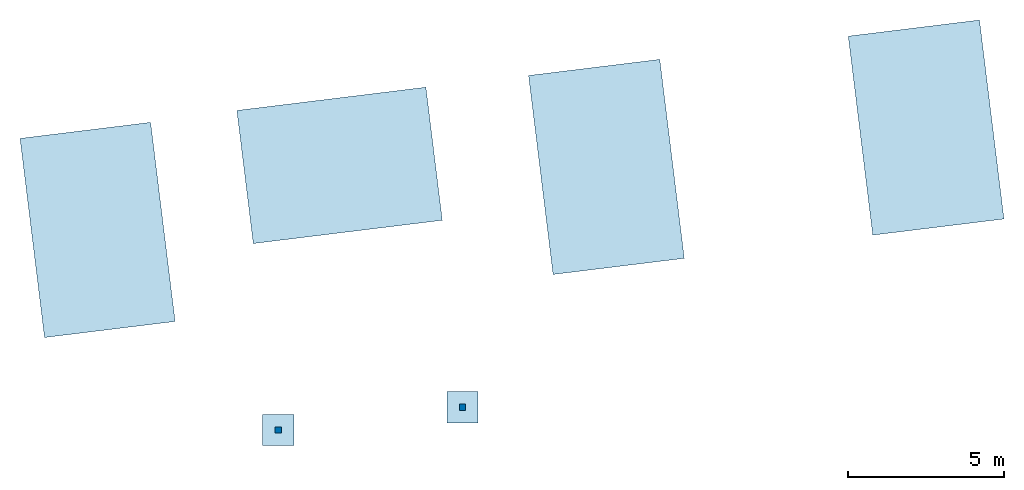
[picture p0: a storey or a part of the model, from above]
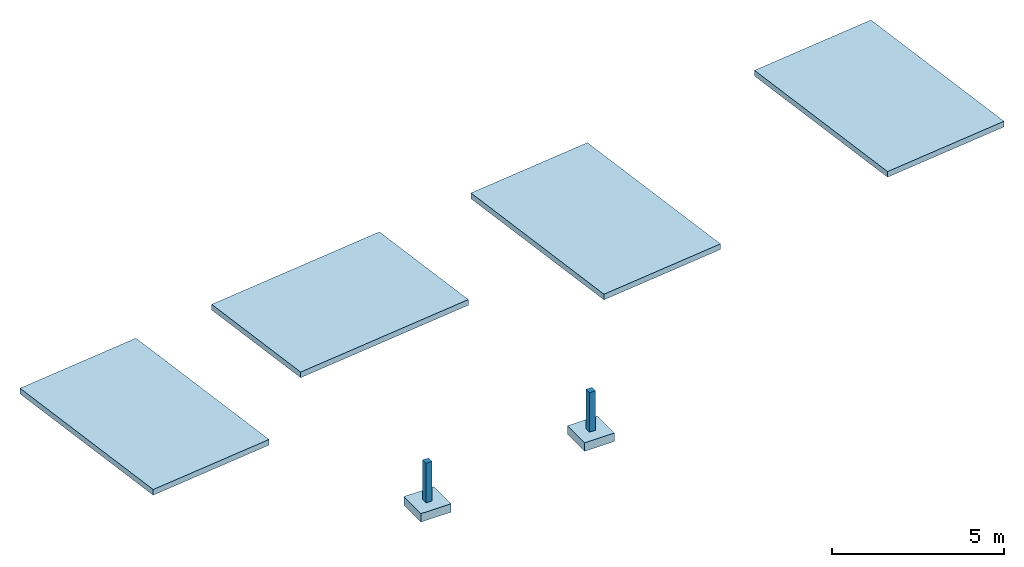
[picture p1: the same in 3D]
Properties of the parts of a building model (IFC2X3)

# File
Description: ViewDefinition [CoordinationView]
Time: 2023-04-20T00:44:39
Made in: SketchUp Pro 2015

# IfcProject, 1013 - PRAÇA - RANCHO QUEIMADO
Description: 1013 - PRAÇA - RANCHO QUEIMADO

# IfcSite, Default Site
Description: Description of Default Site; RefLatitude: 24, 28, 0; RefLongitude: 54, 25, 0; RefElevation: 10 mm

# IfcBuilding, Default Building
Description: Description of Default Building

# IfcBuildingStorey (3)
In: Default Building
Description: Description of Default Building Storey; Elevation: 0 mm

# IfcBeam (4)
In: Fundação
Description: Description of Object
Description - IfcText: Retangular. Concreto armado
PSet_BeamCommon - isExternal: no; isLoadBearing: yes
Name | ObjectType, IfcLabel | Name, IfcLabel
IfcBeam - IfcBeam - Viga 118 (60x150) | 60x150 | Viga 118 (60x150)
IfcBeam - Viga 123 (30x70) | 30x70 | Viga 123 (30x70)
IfcBeam - Viga 122 (30x70) | 30x70 | Viga 122 (30x70)
IfcBeam - Viga 124 (30x70) | 30x70 | Viga 124 (30x70)

# IfcColumn (8)
In: Fundação
Description: Description of Object
Description - IfcText: Retangular. Concreto armado
PSet_ColumnCommon - isExternal: no; isLoadBearing: yes
Qto_ColumnBaseQuantities - Length: 1200
Name | ObjectType, IfcLabel | Name, IfcLabel | Reference
IfcColumn - IfcColumn - P1 (20x20) | 20x20 | P1 (20x20) | P1
IfcColumn - IfcColumn - P2 (20x20) | 20x20 | P2 (20x20) | P2
IfcColumn - P6 (40x40) | 40x40 | P6 (40x40) | P6
IfcColumn - P5 (40x40) | 40x40 | P5 (40x40) | P5
IfcColumn - P8 (40x40) | 40x40 | P8 (40x40) | P8
IfcColumn - P3 (40x40) | 40x40 | P3 (40x40) | P3
IfcColumn - P4 (40x40) | 40x40 | P4 (40x40) | P4
IfcColumn - P7 (40x40) | 40x40 | P7 (40x40) | P7

# IfcFooting (131)
In: Fundação
Description: Description of Object
PredefinedType - IfcFootingTypeEnum: footing_beam
Name | ObjectType, IfcLabel | Name, IfcLabel | IfcText
IfcFooting - IfcFooting - P1 (100 x 100 x 30) | 100 x 100 x 30 | P1 (100 x 100 x 30) | Sapata em concreto armado
IfcFooting - IfcFooting - P2 (100 x 100 x 30) | 100 x 100 x 30 | P2 (100 x 100 x 30) | Sapata em concreto armado
IfcFooting - IfcFooting - Viga 34 (50x30) | 50x30 | Viga 34 (50x30) | Retangular. Concreto armado
IfcFooting - IfcFooting - Viga 23 (50x30) | 50x30 | Viga 23 (50x30) | Retangular. Concreto armado
IfcFooting - IfcFooting - Viga 26 (50x30) | 50x30 | Viga 26 (50x30) | Retangular. Concreto armado
IfcFooting - IfcFooting - Viga 31 (50x30) | 50x30 | Viga 31 (50x30) | Retangular. Concreto armado
IfcFooting - IfcFooting - Viga 39 (50x30) | 50x30 | Viga 39 (50x30) | Retangular. Concreto armado
IfcFooting - IfcFooting - Viga 35 (50x30) | 50x30 | Viga 35 (50x30) | Retangular. Concreto armado
IfcFooting - IfcFooting - Viga 36 (50x30) | 50x30 | Viga 36 (50x30) | Retangular. Concreto armado
IfcFooting - IfcFooting - Viga 42 (50x30) | 50x30 | Viga 42 (50x30) | Retangular. Concreto armado
IfcFooting - IfcFooting - Viga 25 (50x30) | 50x30 | Viga 25 (50x30) | Retangular. Concreto armado
IfcFooting - IfcFooting - Viga 28 (50x30) | 50x30 | Viga 28 (50x30) | Retangular. Concreto armado
IfcFooting - IfcFooting - Viga 43 (50x30) | 50x30 | Viga 43 (50x30) | Retangular. Concreto armado
IfcFooting - IfcFooting - Viga 29 (50x30) | 50x30 | Viga 29 (50x30) | Retangular. Concreto armado
IfcFooting - IfcFooting - Viga 40 (50x30) | 50x30 | Viga 40 (50x30) | Retangular. Concreto armado
IfcFooting - IfcFooting - Viga 33 (50x30) | 50x30 | Viga 33 (50x30) | Retangular. Concreto armado
IfcFooting - IfcFooting - Viga 38 (50x30) | 50x30 | Viga 38 (50x30) | Retangular. Concreto armado
IfcFooting - IfcFooting - Viga 37 (50x30) | 50x30 | Viga 37 (50x30) | Retangular. Concreto armado
IfcFooting - IfcFooting - Viga 24 (50x30) | 50x30 | Viga 24 (50x30) | Retangular. Concreto armado
IfcFooting - IfcFooting - Viga 44 (50x30) | 50x30 | Viga 44 (50x30) | Retangular. Concreto armado
IfcFooting - IfcFooting - Viga 30 (50x30) | 50x30 | Viga 30 (50x30) | Retangular. Concreto armado
IfcFooting - IfcFooting - Viga 27 (50x30) | 50x30 | Viga 27 (50x30) | Retangular. Concreto armado
IfcFooting - IfcFooting - Viga 32 (50x30) | 50x30 | Viga 32 (50x30) | Retangular. Concreto armado
IfcFooting - IfcFooting - Viga 41 (50x30) | 50x30 | Viga 41 (50x30) | Retangular. Concreto armado
IfcFooting - IfcFooting - Viga 45 (50x30) | 50x30 | Viga 45 (50x30) | Retangular. Concreto armado
IfcFooting - IfcFooting - Viga 119 (60x100) |  | Viga 119 (60x100) | Retangular. Concreto armado
IfcFooting - IfcFooting - Viga 83 (50x30) | 50x30 | Viga 83 (50x30) | Retangular. Concreto armado
IfcFooting - IfcFooting - Viga 82 (50x30) | 50x30 | Viga 82 (50x30) | Retangular. Concreto armado
IfcFooting - IfcFooting - Viga 87 (50x30) | 50x30 | Viga 87 (50x30) | Retangular. Concreto armado
IfcFooting - IfcFooting - Viga 94 (50x30) | 50x30 | Viga 94 (50x30) | Retangular. Concreto armado
IfcFooting - IfcFooting - Viga 91 (50x30) | 50x30 | Viga 91 (50x30) | Retangular. Concreto armado
2 x IfcFooting - IfcFooting - Viga 85 (50x30) | 50x30 | Viga 85 (50x30) | Retangular. Concreto armado
IfcFooting - IfcFooting - Viga 86 (50x30) | 50x30 | Viga 86 (50x30) | Retangular. Concreto armado
IfcFooting - IfcFooting - Viga 92 (50x30) | 50x30 | Viga 92 (50x30) | Retangular. Concreto armado
IfcFooting - IfcFooting - Viga 84 (50x30) | 50x30 | Viga 84 (50x30) | Retangular. Concreto armado
IfcFooting - IfcFooting - Viga 88 (50x30) | 50x30 | Viga 88 (50x30) | Retangular. Concreto armado
IfcFooting - IfcFooting - Viga 89 (50x30) | 50x30 | Viga 89 (50x30) | Retangular. Concreto armado
IfcFooting - IfcFooting - Viga 90 (50x30) | 50x30 | Viga 90 (50x30) | Retangular. Concreto armado
IfcFooting - IfcFooting - Viga 81 (50x30) | 50x30 | Viga 81 (50x30) | Retangular. Concreto armado
IfcFooting - IfcFooting - Viga 93 (50x30) | 50x30 | Viga 93 (50x30) | Retangular. Concreto armado
IfcFooting - IfcFooting - Viga 80 (50x30) | 50x30 | Viga 80 (50x30) | Retangular. Concreto armado
IfcFooting - IfcFooting - Viga 74 (50x30) | 50x30 | Viga 74 (50x30) | Retangular. Concreto armado
IfcFooting - IfcFooting - Viga 75 (50x30) | 50x30 | Viga 75 (50x30) | Retangular. Concreto armado
IfcFooting - IfcFooting - Viga 72 (50x30) | 50x30 | Viga 72 (50x30) | Retangular. Concreto armado
IfcFooting - IfcFooting - Viga 71 (50x30) | 50x30 | Viga 71 (50x30) | Retangular. Concreto armado
IfcFooting - IfcFooting - Viga 73 (50x30) | 50x30 | Viga 73 (50x30) | Retangular. Concreto armado
IfcFooting - IfcFooting - Viga 78 (50x30) | 50x30 | Viga 78 (50x30) | Retangular. Concreto armado
IfcFooting - IfcFooting - Viga 76 (50x30) | 50x30 | Viga 76 (50x30) | Retangular. Concreto armado
IfcFooting - IfcFooting - Viga 79 (50x30) | 50x30 | Viga 79 (50x30) | Retangular. Concreto armado
IfcFooting - IfcFooting - Viga 77 (50x30) | 50x30 | Viga 77 (50x30) | Retangular. Concreto armado
IfcFooting - IfcFooting - Viga 70 (50x30) | 50x30 | Viga 70 (50x30) | Retangular. Concreto armado
IfcFooting - IfcFooting - Viga 49 (110/30) | 110/30 | Viga 49 (110/30) | Viga de fundação. Concreto armado
IfcFooting - IfcFooting - Viga 51 (110/30) | 110/30 | Viga 51 (110/30) | Viga de fundação. Concreto armado
IfcFooting - IfcFooting - Viga 47 (110/30) | 110/30 | Viga 47 (110/30) | Viga de fundação. Concreto armado
IfcFooting - IfcFooting - Viga 50 (110/30) | 110/30 | Viga 50 (110/30) | Viga de fundação. Concreto armado
IfcFooting - IfcFooting - Viga 46 (110/30) | 110/30 | Viga 46 (110/30) | Viga de fundação. Concreto armado
IfcFooting - IfcFooting - Viga 53 (110/30) | 110/30 | Viga 53 (110/30) | Viga de fundação. Concreto armado
IfcFooting - IfcFooting - Viga 48 (110/30) | 110/30 | Viga 48 (110/30) | Viga de fundação. Concreto armado
IfcFooting - IfcFooting - Viga 52 (110/30) | 110/30 | Viga 52 (110/30) | Viga de fundação. Concreto armado
IfcFooting - IfcFooting - Viga 65 (110/30) | 110/30 | Viga 65 (110/30) | Viga de fundação. Concreto armado
IfcFooting - IfcFooting - Viga 66 (110/30) | 110/30 | Viga 66 (110/30) | Viga de fundação. Concreto armado
IfcFooting - IfcFooting - Viga 67 (110/30) | 110/30 | Viga 67 (110/30) | Viga de fundação. Concreto armado
IfcFooting - IfcFooting - Viga 64 (110/30) | 110/30 | Viga 64 (110/30) | Viga de fundação. Concreto armado
IfcFooting - IfcFooting - Viga 54 (110/30) | 110/30 | Viga 54 (110/30) | Viga de fundação. Concreto armado
IfcFooting - IfcFooting - Viga 62 (110/30) | 110/30 | Viga 62 (110/30) | Viga de fundação. Concreto armado
IfcFooting - IfcFooting - Viga 55 (110/30) | 110/30 | Viga 55 (110/30) | Viga de fundação. Concreto armado
IfcFooting - IfcFooting - Viga 63 (110/30) | 110/30 | Viga 63 (110/30) | Viga de fundação. Concreto armado
IfcFooting - IfcFooting - Viga 60 (110/30) | 110/30 | Viga 60 (110/30) | Viga de fundação. Concreto armado
IfcFooting - IfcFooting - Viga 58 (110/30) | 110/30 | Viga 58 (110/30) | Viga de fundação. Concreto armado
IfcFooting - IfcFooting - Viga 61 (110/30) | 110/30 | Viga 61 (110/30) | Viga de fundação. Concreto armado
IfcFooting - IfcFooting - Viga 68 (110/30) | 110/30 | Viga 68 (110/30) | Viga de fundação. Concreto armado
IfcFooting - IfcFooting - Viga 59 (110/30) | 110/30 | Viga 59 (110/30) | Viga de fundação. Concreto armado
IfcFooting - IfcFooting - Viga 69 (110/30) | 110/30 | Viga 69 (110/30) | Viga de fundação. Concreto armado
IfcFooting - IfcFooting - Viga 56 (110/30) | 110/30 | Viga 56 (110/30) | Viga de fundação. Concreto armado
IfcFooting - IfcFooting - Viga 57 (110/30) | 110/30 | Viga 57 (110/30) | Viga de fundação. Concreto armado
IfcFooting - IfcFooting - Viga 197 (110/30) | 110/30 | Viga 197 (110/30) | Viga de fundação. Concreto armado
IfcFooting - IfcFooting - Viga 198 (110/30) | 110/30 | Viga 198 (110/30) | Viga de fundação. Concreto armado
IfcFooting - IfcFooting - Viga 195 (110/30) | 110/30 | Viga 195 (110/30) | Viga de fundação. Concreto armado
IfcFooting - IfcFooting - Viga 196 (110/30) | 110/30 | Viga 196 (110/30) | Viga de fundação. Concreto armado
IfcFooting - IfcFooting - Viga 1 (110/30) | 110/30 | Viga 1 (110/30) | Viga de fundação. Concreto armado
IfcFooting - IfcFooting - Viga 12 (110/30) | 110/30 | Viga 12 (110/30) | Viga de fundação. Concreto armado
IfcFooting - IfcFooting - Viga 7 (110/30) | 110/30 | Viga 7 (110/30) | Viga de fundação. Concreto armado
IfcFooting - IfcFooting - Viga 17 (110/30) | 110/30 | Viga 17 (110/30) | Viga de fundação. Concreto armado
IfcFooting - IfcFooting - Viga 2 (110/30) | 110/30 | Viga 2 (110/30) | Viga de fundação. Concreto armado
IfcFooting - IfcFooting - Viga 4 (110/30) | 110/30 | Viga 4 (110/30) | Viga de fundação. Concreto armado
IfcFooting - IfcFooting - Viga 8 (110/30) | 110/30 | Viga 8 (110/30) | Viga de fundação. Concreto armado
IfcFooting - IfcFooting - Viga 22 (110/30) | 110/30 | Viga 22 (110/30) | Viga de fundação. Concreto armado
IfcFooting - IfcFooting - Viga 20 (110/30) | 110/30 | Viga 20 (110/30) | Viga de fundação. Concreto armado
IfcFooting - IfcFooting - Viga 9 (110/30) | 110/30 | Viga 9 (110/30) | Viga de fundação. Concreto armado
IfcFooting - IfcFooting - Viga 21 (110/30) | 110/30 | Viga 21 (110/30) | Viga de fundação. Concreto armado
IfcFooting - IfcFooting - Viga 14 (110/30) | 110/30 | Viga 14 (110/30) | Viga de fundação. Concreto armado
IfcFooting - IfcFooting - Viga 15 (110/30) | 110/30 | Viga 15 (110/30) | Viga de fundação. Concreto armado
IfcFooting - IfcFooting - Viga 6 (110/30) | 110/30 | Viga 6 (110/30) | Viga de fundação. Concreto armado
IfcFooting - IfcFooting - Viga 16 (110/30) | 110/30 | Viga 16 (110/30) | Viga de fundação. Concreto armado
IfcFooting - IfcFooting - Viga 3 (110/30) | 110/30 | Viga 3 (110/30) | Viga de fundação. Concreto armado
IfcFooting - IfcFooting - Viga 19 (110/30) | 110/30 | Viga 19 (110/30) | Viga de fundação. Concreto armado
IfcFooting - IfcFooting - Viga 5 (110/30) | 110/30 | Viga 5 (110/30) | Viga de fundação. Concreto armado
IfcFooting - IfcFooting - Viga 13 (110/30) | 110/30 | Viga 13 (110/30) | Viga de fundação. Concreto armado
IfcFooting - IfcFooting - Viga 18 (110/30) | 110/30 | Viga 18 (110/30) | Viga de fundação. Concreto armado
IfcFooting - IfcFooting - Viga 11 (110/30) | 110/30 | Viga 11 (110/30) | Viga de fundação. Concreto armado
IfcFooting - IfcFooting - Viga 10 (110/30) | 110/30 | Viga 10 (110/30) | Viga de fundação. Concreto armado
IfcFooting - IfcFooting - Viga 113 (110/30) | 110/30 | Viga 113 (110/30) | Viga de fundação. Concreto armado
IfcFooting - IfcFooting - Viga 103 (110/30) | 110/30 | Viga 103 (110/30) | Viga de fundação. Concreto armado
IfcFooting - IfcFooting - Viga 112 (110/30) | 110/30 | Viga 112 (110/30) | Viga de fundação. Concreto armado
IfcFooting - IfcFooting - Viga 100 (110/30) | 110/30 | Viga 100 (110/30) | Viga de fundação. Concreto armado
IfcFooting - IfcFooting - Viga 99 (110/30) | 110/30 | Viga 99 (110/30) | Viga de fundação. Concreto armado
IfcFooting - IfcFooting - Viga 111 (110/30) | 110/30 | Viga 111 (110/30) | Viga de fundação. Concreto armado
IfcFooting - IfcFooting - Viga 101 (110/30) | 110/30 | Viga 101 (110/30) | Viga de fundação. Concreto armado
IfcFooting - IfcFooting - Viga 109 (110/30) | 110/30 | Viga 109 (110/30) | Viga de fundação. Concreto armado
IfcFooting - IfcFooting - Viga 102 (110/30) | 110/30 | Viga 102 (110/30) | Viga de fundação. Concreto armado
IfcFooting - IfcFooting - Viga 110 (110/30) | 110/30 | Viga 110 (110/30) | Viga de fundação. Concreto armado
IfcFooting - IfcFooting - Viga 96 (110/30) | 110/30 | Viga 96 (110/30) | Viga de fundação. Concreto armado
IfcFooting - IfcFooting - Viga 115 (110/30) | 110/30 | Viga 115 (110/30) | Viga de fundação. Concreto armado
IfcFooting - IfcFooting - Viga 98 (110/30) | 110/30 | Viga 98 (110/30) | Viga de fundação. Concreto armado
IfcFooting - IfcFooting - Viga 104 (110/30) | 110/30 | Viga 104 (110/30) | Viga de fundação. Concreto armado
IfcFooting - IfcFooting - Viga 108 (110/30) | 110/30 | Viga 108 (110/30) | Viga de fundação. Concreto armado
IfcFooting - IfcFooting - Viga 117 (110/30) | 110/30 | Viga 117 (110/30) | Viga de fundação. Concreto armado
IfcFooting - IfcFooting - Viga 114 (110/30) | 110/30 | Viga 114 (110/30) | Viga de fundação. Concreto armado
IfcFooting - IfcFooting - Viga 107 (110/30) | 110/30 | Viga 107 (110/30) | Viga de fundação. Concreto armado
IfcFooting - IfcFooting - Viga 116 (110/30) | 110/30 | Viga 116 (110/30) | Viga de fundação. Concreto armado
IfcFooting - IfcFooting - Viga 105 (110/30) | 110/30 | Viga 105 (110/30) | Viga de fundação. Concreto armado
IfcFooting - IfcFooting - Viga 95 (110/30) | 110/30 | Viga 95 (110/30) | Viga de fundação. Concreto armado
IfcFooting - IfcFooting - Viga 106 (110/30) | 110/30 | Viga 106 (110/30) | Viga de fundação. Concreto armado
IfcFooting - IfcFooting - Viga 97 (110/30) | 110/30 | Viga 97 (110/30) | Viga de fundação. Concreto armado
IfcFooting - P3 (150 x 150 x 30) | 150 x 150 x 30 | P3 (150 x 150 x 30) | Sapata em concreto armado
IfcFooting - P7 (150 x 150 x 30) | 150 x 150 x 30 | P7 (150 x 150 x 30) | Sapata em concreto armado
IfcFooting - P5 (150 x 150 x 30) | 150 x 150 x 30 | P5 (150 x 150 x 30) | Sapata em concreto armado
IfcFooting - P8 (150 x 150 x 30) | 150 x 150 x 30 | P8 (150 x 150 x 30) | Sapata em concreto armado
IfcFooting - P6 (150 x 150 x 30) | 150 x 150 x 30 | P6 (150 x 150 x 30) | Sapata em concreto armado
IfcFooting - P4 (150 x 150 x 30) | 150 x 150 x 30 | P4 (150 x 150 x 30) | Sapata em concreto armado

# IfcSlab (4)
In: Fundação
Description: Description of Object
PredefinedType - IfcSlabTypeEnum: floor
ObjectType - IfcLabel: Lajes de fundação: 20
Description - IfcText: Lajes de fundação
PSet_SlabCommon - isExternal: no; isLoadBearing: yes
Qto_SlabBaseQuantities - Width: 200
Name | IfcLabel | ConcreteSurface = GrossArea = NetArea | ConcreteVolume = GrossVolume = NetVolume | Perimeter | GrossWeight = NetWeight
IfcSlab - IfcSlab - Pano 2 (20 cm) | Pano 2 (20 cm) | 27.0783 | 5.41566 | 21279 | 13539.2
IfcSlab - IfcSlab - Pano 3 (20 cm) | Pano 3 (20 cm) | 26.1966 | 5.23932 | 20789 | 13098.3
IfcSlab - IfcSlab - Pano 4 (20 cm) | Pano 4 (20 cm) | 27.189 | 5.4378 | 21310.1 | 13594.5
IfcSlab - IfcSlab - Pano 5 (20 cm) | Pano 5 (20 cm) | 27.189 | 5.4378 | 21310.1 | 13594.5

# IfcWallStandardCase (121)
In: Fundação
Description: Description of Object
Description - IfcText: Cortina de concreto armado
PSet_WallCommon - isExternal: no; isLoadBearing: yes
Name | ObjectType, IfcLabel | Name, IfcLabel
IfcWallStandardCase - IfcWallStandardCase - C25 (50) | 50 | C25 (50)
IfcWallStandardCase - IfcWallStandardCase - C28 (50) | 50 | C28 (50)
IfcWallStandardCase - IfcWallStandardCase - C27 (50) | 50 | C27 (50)
IfcWallStandardCase - IfcWallStandardCase - C26 (50) | 50 | C26 (50)
IfcWallStandardCase - IfcWallStandardCase - C29 (50) | 50 | C29 (50)
IfcWallStandardCase - IfcWallStandardCase - C36 (50) | 50 | C36 (50)
IfcWallStandardCase - IfcWallStandardCase - C45 (50) | 50 | C45 (50)
IfcWallStandardCase - IfcWallStandardCase - C39 (50) | 50 | C39 (50)
IfcWallStandardCase - IfcWallStandardCase - C37 (50) | 50 | C37 (50)
IfcWallStandardCase - IfcWallStandardCase - C38 (50) | 50 | C38 (50)
IfcWallStandardCase - IfcWallStandardCase - C40 (50) | 50 | C40 (50)
IfcWallStandardCase - IfcWallStandardCase - C47 (50) | 50 | C47 (50)
IfcWallStandardCase - IfcWallStandardCase - C41 (50) | 50 | C41 (50)
IfcWallStandardCase - IfcWallStandardCase - C44 (50) | 50 | C44 (50)
IfcWallStandardCase - IfcWallStandardCase - C43 (50) | 50 | C43 (50)
IfcWallStandardCase - IfcWallStandardCase - C42 (50) | 50 | C42 (50)
IfcWallStandardCase - IfcWallStandardCase - C46 (50) | 50 | C46 (50)
IfcWallStandardCase - IfcWallStandardCase - C30 (50) | 50 | C30 (50)
IfcWallStandardCase - IfcWallStandardCase - C31 (50) | 50 | C31 (50)
IfcWallStandardCase - IfcWallStandardCase - C32 (50) | 50 | C32 (50)
IfcWallStandardCase - IfcWallStandardCase - C33 (50) | 50 | C33 (50)
IfcWallStandardCase - IfcWallStandardCase - C34 (50) | 50 | C34 (50)
IfcWallStandardCase - IfcWallStandardCase - C35 (50) | 50 | C35 (50)
IfcWallStandardCase - IfcWallStandardCase - C85 (50) | 50 | C85 (50)
IfcWallStandardCase - IfcWallStandardCase - C77 (50) | 50 | C77 (50)
IfcWallStandardCase - IfcWallStandardCase - C72 (50) | 50 | C72 (50)
IfcWallStandardCase - IfcWallStandardCase - C83 (50) | 50 | C83 (50)
IfcWallStandardCase - IfcWallStandardCase - C79 (50) | 50 | C79 (50)
IfcWallStandardCase - IfcWallStandardCase - C87 (50) | 50 | C87 (50)
IfcWallStandardCase - IfcWallStandardCase - C82 (50) | 50 | C82 (50)
IfcWallStandardCase - IfcWallStandardCase - C75 (50) | 50 | C75 (50)
IfcWallStandardCase - IfcWallStandardCase - C74 (50) | 50 | C74 (50)
IfcWallStandardCase - IfcWallStandardCase - C76 (50) | 50 | C76 (50)
IfcWallStandardCase - IfcWallStandardCase - C84 (50) | 50 | C84 (50)
IfcWallStandardCase - IfcWallStandardCase - C78 (50) | 50 | C78 (50)
IfcWallStandardCase - IfcWallStandardCase - C86 (50) | 50 | C86 (50)
IfcWallStandardCase - IfcWallStandardCase - C73 (50) | 50 | C73 (50)
IfcWallStandardCase - IfcWallStandardCase - C80 (50) | 50 | C80 (50)
IfcWallStandardCase - IfcWallStandardCase - C81 (50) | 50 | C81 (50)
IfcWallStandardCase - IfcWallStandardCase - C89 (50) | 50 | C89 (50)
IfcWallStandardCase - IfcWallStandardCase - C90 (50) | 50 | C90 (50)
IfcWallStandardCase - IfcWallStandardCase - C91 (50) | 50 | C91 (50)
IfcWallStandardCase - IfcWallStandardCase - C92 (50) | 50 | C92 (50)
IfcWallStandardCase - IfcWallStandardCase - C88 (50) | 50 | C88 (50)
IfcWallStandardCase - IfcWallStandardCase - C93 (50) | 50 | C93 (50)
IfcWallStandardCase - IfcWallStandardCase - C96 (50) | 50 | C96 (50)
IfcWallStandardCase - IfcWallStandardCase - C94 (50) | 50 | C94 (50)
IfcWallStandardCase - IfcWallStandardCase - C95 (50) | 50 | C95 (50)
IfcWallStandardCase - IfcWallStandardCase - C49 (35) | 35 | C49 (35)
IfcWallStandardCase - IfcWallStandardCase - C48 (35) | 35 | C48 (35)
IfcWallStandardCase - IfcWallStandardCase - C50 (35) | 35 | C50 (35)
IfcWallStandardCase - IfcWallStandardCase - C51 (35) | 35 | C51 (35)
IfcWallStandardCase - IfcWallStandardCase - C52 (35) | 35 | C52 (35)
IfcWallStandardCase - IfcWallStandardCase - C53 (35) | 35 | C53 (35)
IfcWallStandardCase - IfcWallStandardCase - C63 (35) | 35 | C63 (35)
IfcWallStandardCase - IfcWallStandardCase - C54 (35) | 35 | C54 (35)
IfcWallStandardCase - IfcWallStandardCase - C56 (35) | 35 | C56 (35)
IfcWallStandardCase - IfcWallStandardCase - C57 (35) | 35 | C57 (35)
IfcWallStandardCase - IfcWallStandardCase - C58 (35) | 35 | C58 (35)
IfcWallStandardCase - IfcWallStandardCase - C60 (35) | 35 | C60 (35)
IfcWallStandardCase - IfcWallStandardCase - C71 (35) | 35 | C71 (35)
IfcWallStandardCase - IfcWallStandardCase - C69 (35) | 35 | C69 (35)
IfcWallStandardCase - IfcWallStandardCase - C62 (35) | 35 | C62 (35)
IfcWallStandardCase - IfcWallStandardCase - C70 (35) | 35 | C70 (35)
IfcWallStandardCase - IfcWallStandardCase - C59 (35) | 35 | C59 (35)
IfcWallStandardCase - IfcWallStandardCase - C61 (35) | 35 | C61 (35)
IfcWallStandardCase - IfcWallStandardCase - C64 (35) | 35 | C64 (35)
IfcWallStandardCase - IfcWallStandardCase - C65 (35) | 35 | C65 (35)
IfcWallStandardCase - IfcWallStandardCase - C68 (35) | 35 | C68 (35)
IfcWallStandardCase - IfcWallStandardCase - C67 (35) | 35 | C67 (35)
IfcWallStandardCase - IfcWallStandardCase - C55 (35) | 35 | C55 (35)
IfcWallStandardCase - IfcWallStandardCase - C66 (35) | 35 | C66 (35)
IfcWallStandardCase - IfcWallStandardCase - C24 (35) | 35 | C24 (35)
IfcWallStandardCase - IfcWallStandardCase - C12 (35) | 35 | C12 (35)
IfcWallStandardCase - IfcWallStandardCase - C13 (35) | 35 | C13 (35)
IfcWallStandardCase - IfcWallStandardCase - C20 (35) | 35 | C20 (35)
IfcWallStandardCase - IfcWallStandardCase - C14 (35) | 35 | C14 (35)
IfcWallStandardCase - IfcWallStandardCase - C19 (35) | 35 | C19 (35)
IfcWallStandardCase - IfcWallStandardCase - C4 (35) | 35 | C4 (35)
IfcWallStandardCase - IfcWallStandardCase - C10 (35) | 35 | C10 (35)
IfcWallStandardCase - IfcWallStandardCase - C18 (35) | 35 | C18 (35)
IfcWallStandardCase - IfcWallStandardCase - C21 (35) | 35 | C21 (35)
IfcWallStandardCase - IfcWallStandardCase - C23 (35) | 35 | C23 (35)
IfcWallStandardCase - IfcWallStandardCase - C1 (35) | 35 | C1 (35)
IfcWallStandardCase - IfcWallStandardCase - C2 (35) | 35 | C2 (35)
IfcWallStandardCase - IfcWallStandardCase - C5 (35) | 35 | C5 (35)
IfcWallStandardCase - IfcWallStandardCase - C6 (35) | 35 | C6 (35)
IfcWallStandardCase - IfcWallStandardCase - C7 (35) | 35 | C7 (35)
IfcWallStandardCase - IfcWallStandardCase - C8 (35) | 35 | C8 (35)
IfcWallStandardCase - IfcWallStandardCase - C9 (35) | 35 | C9 (35)
IfcWallStandardCase - IfcWallStandardCase - C15 (35) | 35 | C15 (35)
IfcWallStandardCase - IfcWallStandardCase - C11 (35) | 35 | C11 (35)
IfcWallStandardCase - IfcWallStandardCase - C3 (35) | 35 | C3 (35)
IfcWallStandardCase - IfcWallStandardCase - C22 (35) | 35 | C22 (35)
IfcWallStandardCase - IfcWallStandardCase - C120 (35) | 35 | C120 (35)
IfcWallStandardCase - IfcWallStandardCase - C16 (35) | 35 | C16 (35)
IfcWallStandardCase - IfcWallStandardCase - C17 (35) | 35 | C17 (35)
IfcWallStandardCase - IfcWallStandardCase - C121 (35) | 35 | C121 (35)
IfcWallStandardCase - IfcWallStandardCase - C102 (35) | 35 | C102 (35)
IfcWallStandardCase - IfcWallStandardCase - C101 (35) | 35 | C101 (35)
IfcWallStandardCase - IfcWallStandardCase - C98 (35) | 35 | C98 (35)
IfcWallStandardCase - IfcWallStandardCase - C105 (35) | 35 | C105 (35)
IfcWallStandardCase - IfcWallStandardCase - C103 (35) | 35 | C103 (35)
IfcWallStandardCase - IfcWallStandardCase - C97 (35) | 35 | C97 (35)
IfcWallStandardCase - IfcWallStandardCase - C104 (35) | 35 | C104 (35)
IfcWallStandardCase - IfcWallStandardCase - C99 (35) | 35 | C99 (35)
IfcWallStandardCase - IfcWallStandardCase - C106 (35) | 35 | C106 (35)
IfcWallStandardCase - IfcWallStandardCase - C100 (35) | 35 | C100 (35)
IfcWallStandardCase - IfcWallStandardCase - C107 (35) | 35 | C107 (35)
IfcWallStandardCase - IfcWallStandardCase - C109 (35) | 35 | C109 (35)
IfcWallStandardCase - IfcWallStandardCase - C108 (35) | 35 | C108 (35)
IfcWallStandardCase - IfcWallStandardCase - C110 (35) | 35 | C110 (35)
IfcWallStandardCase - IfcWallStandardCase - C111 (35) | 35 | C111 (35)
IfcWallStandardCase - IfcWallStandardCase - C112 (35) | 35 | C112 (35)
IfcWallStandardCase - IfcWallStandardCase - C113 (35) | 35 | C113 (35)
IfcWallStandardCase - IfcWallStandardCase - C114 (35) | 35 | C114 (35)
IfcWallStandardCase - IfcWallStandardCase - C115 (35) | 35 | C115 (35)
IfcWallStandardCase - IfcWallStandardCase - C116 (35) | 35 | C116 (35)
IfcWallStandardCase - IfcWallStandardCase - C117 (35) | 35 | C117 (35)
IfcWallStandardCase - IfcWallStandardCase - C118 (35) | 35 | C118 (35)
IfcWallStandardCase - IfcWallStandardCase - C119 (35) | 35 | C119 (35)
